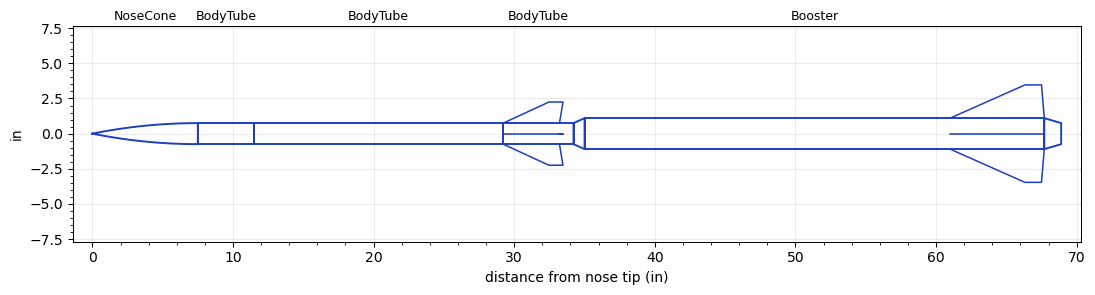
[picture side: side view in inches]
<RASAeroDocument>
 <FileVersion>2</FileVersion>
 <RocketDesign>
  <NoseCone>
   <Length>7.5</Length>
   <Diameter>1.4961</Diameter>
   <Shape>Tangent Ogive</Shape>
   <BluntRadius>0.065</BluntRadius>
   <Location>0</Location>
  </NoseCone>
  <BodyTube>
   <Length>4</Length>
   <Diameter>1.4961</Diameter>
   <Location>7.5</Location>
  </BodyTube>
  <BodyTube>
   <Length>17.71654</Length>
   <Diameter>1.4961</Diameter>
   <Location>11.5</Location>
  </BodyTube>
  <BodyTube>
   <Length>5</Length>
   <Diameter>1.4961</Diameter>
   <Location>29.21654</Location>
   <Fin>
    <Count>4</Count>
    <Chord>4</Chord>
    <Span>1.5</Span>
    <SweepDistance>3.25</SweepDistance>
    <TipChord>1</TipChord>
    <Thickness>0.075</Thickness>
    <LERadius>0.065</LERadius>
    <Location>5</Location>
    <AirfoilSection>Hexagonal</AirfoilSection>
    <FX1>0.25</FX1>
    <FX3>0.25</FX3>
   </Fin>
  </BodyTube>
  <Booster>
   <Length>32.6929</Length>
   <Diameter>2.2047</Diameter>
   <InsideDiameter>1.4961</InsideDiameter>
   <RailGuideDiameter>0.4</RailGuideDiameter>
   <RailGuideHeight>0.5</RailGuideHeight>
   <Location>34.21654</Location>
   <ShoulderLength>0.7874</ShoulderLength>
   <BoattailLength>1.2</BoattailLength>
   <BoattailRearDiameter>1.5</BoattailRearDiameter>
   <Fin>
    <Count>4</Count>
    <Chord>6.6929</Chord>
    <Span>2.3622</Span>
    <SweepDistance>5.315</SweepDistance>
    <TipChord>1.1811</TipChord>
    <Thickness>0.1575</Thickness>
    <LERadius>0.65</LERadius>
    <Location>6.6929</Location>
    <AirfoilSection>Hexagonal</AirfoilSection>
    <FX1>0.75</FX1>
    <FX3>0.75</FX3>
   </Fin>
  </Booster>
  <Surface>Camouflage Paint</Surface>
  <ModifiedBarrowman>True</ModifiedBarrowman>
  <Turbulence>True</Turbulence>
  <UseBooster1>False</UseBooster1>
  <UseBooster2>False</UseBooster2>
 </RocketDesign>
 <LaunchSite>
  <Altitude>2000</Altitude>
  <Pressure>29.9</Pressure>
  <RodAngle>1</RodAngle>
  <RodLength>10</RodLength>
  <Temperature>74</Temperature>
  <WindSpeed>10</WindSpeed>
 </LaunchSite>
 <Recovery>
  <Altitude1>1000</Altitude1>
  <Altitude2>1000</Altitude2>
  <DeviceType1>None</DeviceType1>
  <DeviceType2>None</DeviceType2>
  <Event1>False</Event1>
  <Event2>False</Event2>
  <Size1>1</Size1>
  <Size2>1</Size2>
  <EventType1>None</EventType1>
  <EventType2>None</EventType2>
  <CD1>1.33</CD1>
  <CD2>1.33</CD2>
 </Recovery>
 <SimulationList>
  <Simulation>
   <SustainerEngine>J360  (Walter)</SustainerEngine>
   <SustainerLaunchWt>3.3</SustainerLaunchWt>
   <SustainerNozzleDiameter>1.25</SustainerNozzleDiameter>
   <SustainerCG>21.5</SustainerCG>
   <SustainerIgnitionDelay>7</SustainerIgnitionDelay>
   <Booster1Engine>L416SW  (Walter)</Booster1Engine>
   <Booster1LaunchWt>9.73</Booster1LaunchWt>
   <Booster1SeparationDelay>0</Booster1SeparationDelay>
   <Booster1IgnitionDelay>0</Booster1IgnitionDelay>
   <Booster1CG>44.3</Booster1CG>
   <Booster1NozzleDiameter>1.25</Booster1NozzleDiameter>
   <IncludeBooster1>True</IncludeBooster1>
   <Booster2Delay>0</Booster2Delay>
   <IncludeBooster2>False</IncludeBooster2>
   <TimetoApogee>55.80774</TimetoApogee>
   <MaxAltitude>53889.1</MaxAltitude>
   <MaxVelocity>3066.25</MaxVelocity>
   <OptimumWt>3.3825</OptimumWt>
   <OptimumMaxAlt>3.3825</OptimumMaxAlt>
  </Simulation>
 </SimulationList>
</RASAeroDocument>
